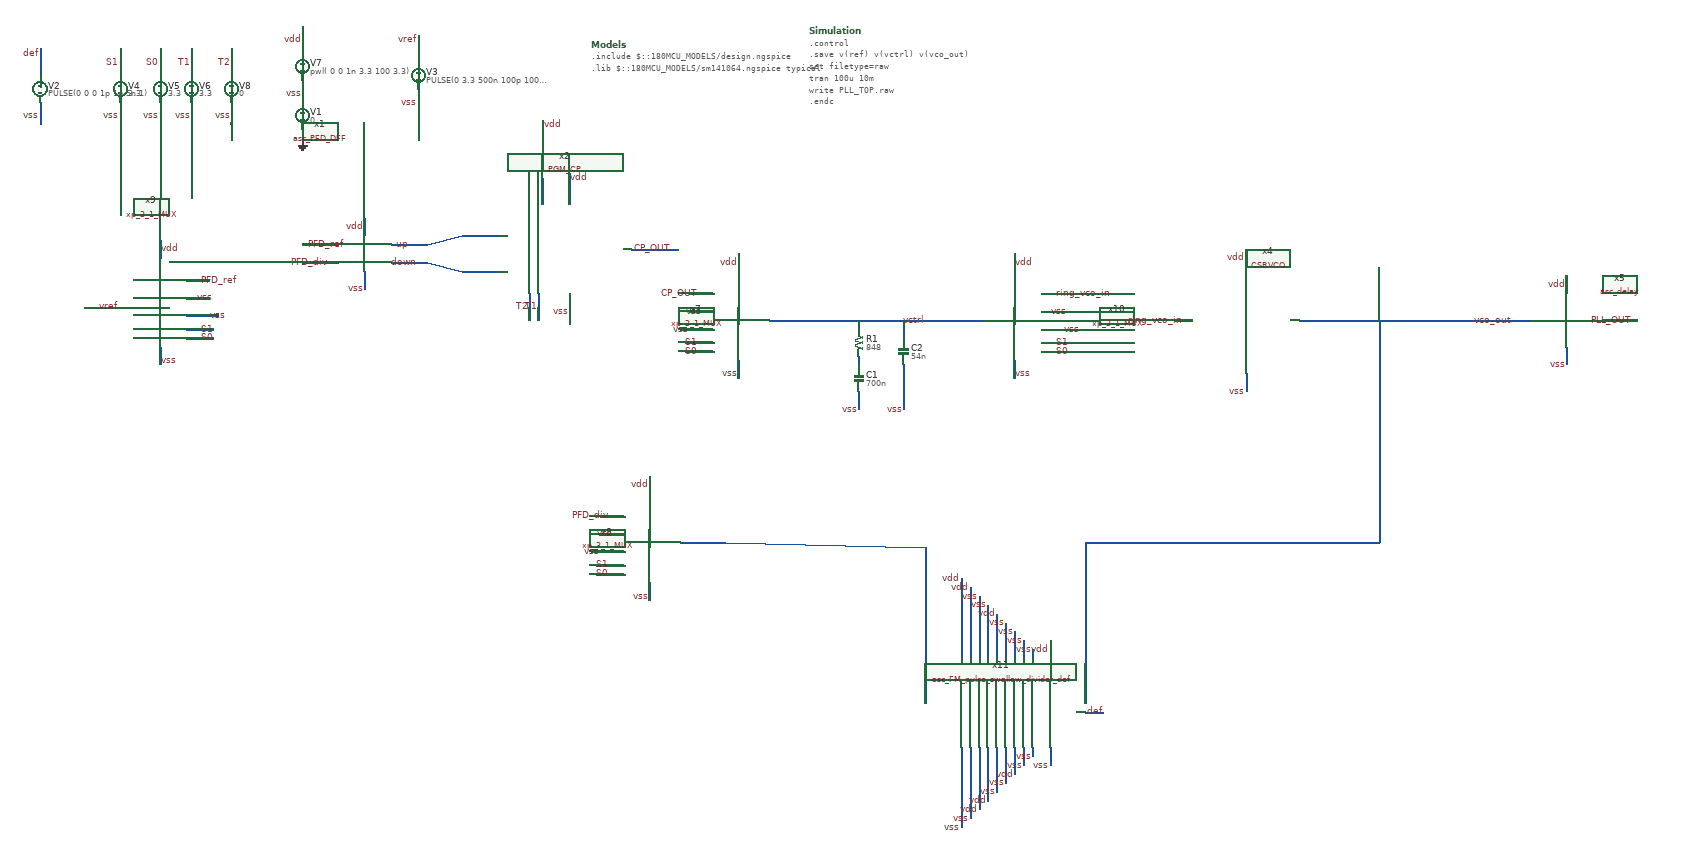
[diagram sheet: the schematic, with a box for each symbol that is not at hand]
v {xschem version=3.4.7 file_version=1.2}
G {}
K {}
V {}
S {}
E {}
N -310 -760 -310 -730 {lab=GND}
N -310 -870 -310 -820 {lab=vss}
N -310 -990 -310 -930 {lab=vdd}
N -50 -850 -50 -800 {lab=vss}
N -50 -970 -50 -910 {lab=vref}
N -270 -500 -230 -500 {lab=PFD_ref}
N -270 -460 -230 -460 {lab=PFD_div}
N -110 -500 -70 -500 {lab=up}
N -110 -460 -70 -460 {lab=down}
N -170 -560 -170 -520 {lab=vdd}
N -170 -440 -170 -400 {lab=vss}
N -70 -500 -30 -500 {lab=up}
N -70 -460 -30 -460 {lab=down}
N 840 -330 880 -330 {lab=vctrl}
N 1930 -330 1990 -330 {lab=vco_out}
N 2610 -330 2690 -330 {lab=PLL_OUT}
N 1990 -330 2070 -330 {lab=vco_out}
N 2530 -430 2530 -390 {lab=vdd}
N 2530 -270 2530 -230 {lab=vss}
N 1810 -210 1810 -170 {lab=vss}
N 1810 -490 1810 -450 {lab=vdd}
N 1650 -330 1690 -330 {lab=ring_vco_in}
N -310 -460 -270 -460 {lab=PFD_div}
N 880 -330 900 -330 {lab=vctrl}
N 900 -330 1120 -330 {lab=vctrl}
N 1040 -230 1040 -190 {lab=vss}
N 940 -170 940 -130 {lab=vss}
N 1040 -190 1040 -130 {lab=vss}
N 1040 -330 1040 -290 {lab=vctrl}
N 940 -250 940 -230 {lab=#net1}
N 940 -330 940 -310 {lab=vctrl}
N 230 -780 230 -710 {lab=vdd}
N 50 -520 90 -520 {lab=up}
N 50 -440 90 -440 {lab=down}
N 90 -520 130 -520 {lab=up}
N 90 -440 130 -440 {lab=down}
N 230 -650 230 -590 {lab=#net2}
N 290 -660 290 -590 {lab=vdd}
N 290 -390 290 -350 {lab=vss}
N -560 -820 -560 -770 {lab=vss}
N -560 -940 -560 -880 {lab=T1}
N -470 -820 -470 -770 {lab=vss}
N -470 -940 -470 -880 {lab=T2}
N 220 -390 220 -330 {lab=T1}
N 200 -390 200 -330 {lab=T2}
N 2070 -330 2450 -330 {lab=vco_out}
N -30 -500 50 -520 {lab=up}
N -30 -460 50 -440 {lab=down}
N 670 -480 670 -440 {lab=vdd}
N 670 -240 670 -200 {lab=vss}
N 430 -490 470 -490 {lab=CP_OUT}
N 470 -490 530 -490 {lab=CP_OUT}
N 560 -390 610 -390 {lab=CP_OUT}
N 560 -350 610 -350 {lab=vss}
N 540 -310 610 -310 {lab=vss}
N -720 -820 -720 -770 {lab=vss}
N -720 -940 -720 -880 {lab=S1}
N -630 -820 -630 -770 {lab=vss}
N -630 -940 -630 -880 {lab=S0}
N 550 -280 610 -280 {lab=S1}
N 550 -260 610 -260 {lab=S0}
N 740 -330 840 -330 {lab=vctrl}
N 470 20 470 60 {lab=vdd}
N 470 260 470 300 {lab=vss}
N 360 110 410 110 {lab=PFD_div}
N 360 150 410 150 {lab=vss}
N 340 190 410 190 {lab=vss}
N 350 220 410 220 {lab=S1}
N 350 240 410 240 {lab=S0}
N 540 170 640 170 {lab=#net3}
N -630 -510 -630 -470 {lab=vdd}
N -630 -270 -630 -230 {lab=vss}
N -570 -420 -520 -420 {lab=PFD_ref}
N -570 -380 -520 -380 {lab=vss}
N -570 -340 -500 -340 {lab=vss}
N -570 -310 -510 -310 {lab=S1}
N -570 -290 -510 -290 {lab=S0}
N -800 -360 -700 -360 {lab=vref}
N -310 -500 -270 -500 {lab=PFD_ref}
N 1290 -480 1290 -440 {lab=vdd}
N 1290 -240 1290 -200 {lab=vss}
N 1350 -390 1400 -390 {lab=ring_vco_in}
N 1350 -350 1400 -350 {lab=vss}
N 1350 -310 1420 -310 {lab=vss}
N 1350 -280 1410 -280 {lab=S1}
N 1350 -260 1410 -260 {lab=S0}
N 1120 -330 1220 -330 {lab=vctrl}
N 2110 -330 2110 160 {lab=vco_out}
N 2110 160 2110 170 {lab=vco_out}
N 1700 170 2110 170 {lab=vco_out}
N -900 -820 -900 -770 {lab=vss}
N -900 -940 -900 -880 {lab=def}
N 1310 630 1310 660 {lab=vss}
N 1310 660 1310 670 {lab=vss}
N 1290 630 1290 670 {lab=vdd}
N 1270 630 1270 670 {lab=vss}
N 1250 630 1250 670 {lab=vss}
N 1230 630 1230 670 {lab=vdd}
N 1210 630 1210 670 {lab=vdd}
N 1170 630 1170 660 {lab=vss}
N 1170 660 1170 670 {lab=vss}
N 1190 630 1190 670 {lab=vss}
N 1170 670 1170 770 {lab=vss}
N 1170 770 1170 790 {lab=vss}
N 1170 790 1170 810 {lab=vss}
N 1190 670 1190 790 {lab=vss}
N 1210 670 1210 770 {lab=vdd}
N 1230 670 1230 750 {lab=vdd}
N 1250 670 1250 730 {lab=vss}
N 1270 670 1270 710 {lab=vss}
N 1290 670 1290 690 {lab=vdd}
N 1330 630 1330 650 {lab=vss}
N 1450 550 1490 550 {lab=def}
N 1370 390 1370 430 {lab=vdd}
N 1370 630 1370 670 {lab=vss}
N 1330 410 1330 430 {lab=vss}
N 1310 390 1310 430 {lab=vss}
N 1290 370 1290 430 {lab=vss}
N 1270 350 1270 430 {lab=vss}
N 1250 330 1250 430 {lab=vdd}
N 1230 310 1230 430 {lab=vss}
N 1210 290 1210 430 {lab=vss}
N 1190 270 1190 430 {lab=vdd}
N 1170 250 1170 430 {lab=vdd}
N 1450 170 1450 530 {lab=vco_out}
N 1450 170 1700 170 {lab=vco_out}
N 1090 180 1090 530 {lab=#net3}
N 640 170 1090 180 {lab=#net3}
C {devices/code_shown.sym} 340 -950 0 0 {name=Models only_toplevel=false
format="tcleval( @value )"
value="
.include $::180MCU_MODELS/design.ngspice
.lib $::180MCU_MODELS/sm141064.ngspice typical
"}
C {devices/code_shown.sym} 830 -980 0 0 {name=Simulation only_toplevel=false value="
.control
.save v(ref) v(vctrl) v(vco_out)
set filetype=raw
tran 100u 10m
write PLL_TOP.raw
.endc
"}
C {devices/vsource.sym} -310 -790 0 0 {name=V1 value=0 savecurrent=false}
C {devices/gnd.sym} -310 -730 0 0 {name=l1 lab=GND}
C {devices/lab_wire.sym} -310 -840 0 0 {name=p2 sig_type=std_logic lab=vss}
C {devices/vsource.sym} -50 -880 0 0 {name=V3
value="PULSE(0 3.3 500n 100p 100p 50u 100u)"
savecurrent=false}
C {devices/lab_wire.sym} -50 -820 0 0 {name=p7 sig_type=std_logic lab=vss}
C {devices/lab_wire.sym} -310 -960 0 0 {name=p4 sig_type=std_logic lab=vdd}
C {devices/lab_wire.sym} -50 -960 0 0 {name=p8 sig_type=std_logic lab=vref}
C {libs/core_analog/asc_PFD_DFF/asc_PFD_DFF.sym} -170 -480 0 0 {name=x1}
C {devices/lab_wire.sym} -170 -400 0 0 {name=p5 sig_type=std_logic lab=vss}
C {devices/lab_wire.sym} -170 -540 0 0 {name=p6 sig_type=std_logic lab=vdd}
C {devices/lab_wire.sym} -70 -500 0 0 {name=p11 sig_type=std_logic lab=up}
C {devices/lab_wire.sym} -50 -460 0 0 {name=p12 sig_type=std_logic lab=down}
C {libs/core_analog/CSRVCO/CSRVCO.sym} 1810 -330 0 0 {name=x4}
C {libs/core_analog/asc_delay/asc_delay.sym} 2530 -330 0 0 {name=x5}
C {devices/lab_wire.sym} 1810 -170 0 0 {name=p17 sig_type=std_logic lab=vss}
C {devices/lab_wire.sym} 2530 -230 0 0 {name=p18 sig_type=std_logic lab=vss}
C {devices/lab_wire.sym} 2680 -330 0 0 {name=p19 sig_type=std_logic lab=PLL_OUT}
C {devices/lab_wire.sym} 1810 -470 0 0 {name=p20 sig_type=std_logic lab=vdd}
C {devices/lab_wire.sym} 2530 -410 0 0 {name=p21 sig_type=std_logic lab=vdd}
C {devices/lab_wire.sym} 2410 -330 0 0 {name=p25 sig_type=std_logic lab=vco_out}
C {devices/capa.sym} 940 -200 0 0 {name=C1
m=1
value=700n
footprint=1206
device="ceramic capacitor"}
C {devices/capa.sym} 1040 -260 0 0 {name=C2
m=1
value=54n
footprint=1206
device="ceramic capacitor"}
C {devices/lab_wire.sym} 1040 -130 0 0 {name=p1 sig_type=std_logic lab=vss}
C {devices/lab_wire.sym} 940 -130 0 0 {name=p3 sig_type=std_logic lab=vss}
C {devices/res.sym} 940 -280 0 0 {name=R1
value=848
footprint=1206
device=resistor
m=1}
C {isource.sym} 230 -680 0 0 {name=I1 value=100u}
C {devices/lab_wire.sym} 230 -770 2 0 {name=p36 sig_type=std_logic lab=vdd}
C {devices/lab_wire.sym} 1090 -330 0 0 {name=p13 sig_type=std_logic lab=vctrl}
C {libs/core_analog/PGM_CP.sym} 280 -490 0 0 {name=x2}
C {devices/lab_wire.sym} 290 -650 2 0 {name=p23 sig_type=std_logic lab=vdd}
C {devices/lab_wire.sym} 290 -350 0 0 {name=p24 sig_type=std_logic lab=vss}
C {devices/vsource.sym} -560 -850 0 0 {name=V6 value=3.3 savecurrent=false}
C {devices/lab_wire.sym} -560 -790 0 0 {name=p41 sig_type=std_logic lab=vss}
C {devices/lab_wire.sym} -560 -910 0 0 {name=p42 sig_type=std_logic lab=T1}
C {devices/vsource.sym} -470 -850 0 0 {name=V8 value=0 savecurrent=false}
C {devices/lab_wire.sym} -470 -790 0 0 {name=p43 sig_type=std_logic lab=vss}
C {devices/lab_wire.sym} -470 -910 0 0 {name=p44 sig_type=std_logic lab=T2}
C {devices/lab_wire.sym} 220 -360 0 0 {name=p26 sig_type=std_logic lab=T1}
C {devices/lab_wire.sym} 200 -360 0 0 {name=p27 sig_type=std_logic lab=T2}
C {libs/core_analog/xp_3_1_MUX.sym} 370 -330 0 0 {name=x7}
C {devices/lab_wire.sym} 670 -460 0 0 {name=p28 sig_type=std_logic lab=vdd}
C {devices/lab_wire.sym} 670 -210 0 0 {name=p29 sig_type=std_logic lab=vss}
C {devices/lab_wire.sym} 520 -490 0 0 {name=p31 sig_type=std_logic lab=CP_OUT}
C {devices/lab_wire.sym} 590 -350 0 0 {name=p32 sig_type=std_logic lab=vss}
C {devices/lab_wire.sym} 580 -390 0 0 {name=p33 sig_type=std_logic lab=CP_OUT}
C {devices/lab_wire.sym} 560 -310 0 0 {name=p34 sig_type=std_logic lab=vss}
C {devices/vsource.sym} -720 -850 0 0 {name=V4 value=3.3 savecurrent=false}
C {devices/lab_wire.sym} -720 -790 0 0 {name=p35 sig_type=std_logic lab=vss}
C {devices/lab_wire.sym} -720 -910 0 0 {name=p37 sig_type=std_logic lab=S1}
C {devices/vsource.sym} -630 -850 0 0 {name=V5 value=3.3 savecurrent=false}
C {devices/lab_wire.sym} -630 -790 0 0 {name=p38 sig_type=std_logic lab=vss}
C {devices/lab_wire.sym} -630 -910 0 0 {name=p39 sig_type=std_logic lab=S0}
C {devices/lab_wire.sym} 580 -280 0 0 {name=p40 sig_type=std_logic lab=S1}
C {devices/lab_wire.sym} 580 -260 0 0 {name=p45 sig_type=std_logic lab=S0}
C {libs/core_analog/xp_3_1_MUX.sym} 170 170 0 0 {name=x8}
C {devices/lab_wire.sym} 470 40 0 0 {name=p47 sig_type=std_logic lab=vdd}
C {devices/lab_wire.sym} 470 290 0 0 {name=p48 sig_type=std_logic lab=vss}
C {devices/lab_wire.sym} 390 150 0 0 {name=p49 sig_type=std_logic lab=vss}
C {devices/lab_wire.sym} 380 110 0 0 {name=p50 sig_type=std_logic lab=PFD_div}
C {devices/lab_wire.sym} 360 190 0 0 {name=p51 sig_type=std_logic lab=vss}
C {devices/lab_wire.sym} 380 220 0 0 {name=p52 sig_type=std_logic lab=S1}
C {devices/lab_wire.sym} 380 240 0 0 {name=p53 sig_type=std_logic lab=S0}
C {devices/lab_wire.sym} -250 -460 0 0 {name=p9 sig_type=std_logic lab=PFD_div}
C {libs/core_analog/xp_3_1_MUX.sym} -330 -360 0 1 {name=x9}
C {devices/lab_wire.sym} -630 -490 0 1 {name=p10 sig_type=std_logic lab=vdd}
C {devices/lab_wire.sym} -630 -240 0 1 {name=p55 sig_type=std_logic lab=vss}
C {devices/lab_wire.sym} -550 -380 0 1 {name=p56 sig_type=std_logic lab=vss}
C {devices/lab_wire.sym} -540 -420 0 1 {name=p57 sig_type=std_logic lab=PFD_ref}
C {devices/lab_wire.sym} -520 -340 0 1 {name=p58 sig_type=std_logic lab=vss}
C {devices/lab_wire.sym} -540 -310 0 1 {name=p59 sig_type=std_logic lab=S1}
C {devices/lab_wire.sym} -540 -290 0 1 {name=p60 sig_type=std_logic lab=S0}
C {devices/lab_wire.sym} -300 -500 0 1 {name=p62 sig_type=std_logic lab=PFD_ref}
C {devices/lab_wire.sym} -770 -360 0 1 {name=p63 sig_type=std_logic lab=vref}
C {libs/core_analog/xp_3_1_MUX.sym} 1590 -330 0 1 {name=x10}
C {devices/lab_wire.sym} 1290 -460 0 1 {name=p46 sig_type=std_logic lab=vdd}
C {devices/lab_wire.sym} 1290 -210 0 1 {name=p64 sig_type=std_logic lab=vss}
C {devices/lab_wire.sym} 1370 -350 0 1 {name=p65 sig_type=std_logic lab=vss}
C {devices/lab_wire.sym} 1380 -390 0 1 {name=p66 sig_type=std_logic lab=ring_vco_in}
C {devices/lab_wire.sym} 1400 -310 0 1 {name=p67 sig_type=std_logic lab=vss}
C {devices/lab_wire.sym} 1380 -280 0 1 {name=p68 sig_type=std_logic lab=S1}
C {devices/lab_wire.sym} 1380 -260 0 1 {name=p69 sig_type=std_logic lab=S0}
C {devices/lab_wire.sym} 1670 -330 2 1 {name=p71 sig_type=std_logic lab=ring_vco_in}
C {devices/vsource.sym} -310 -900 0 0 {name=V7 value="pwl( 0 0 1n 3.3 100 3.3)" savecurrent=false}
C {devices/vsource.sym} -900 -850 0 0 {name=V2
value="PULSE(0 0 0 1p 1p 5n 1)"
savecurrent=false}
C {devices/lab_wire.sym} -900 -790 0 0 {name=p15 sig_type=std_logic lab=vss}
C {devices/lab_wire.sym} -900 -930 0 0 {name=p22 sig_type=std_logic lab=def}
C {devices/lab_wire.sym} 1370 410 0 0 {name=p70 sig_type=std_logic lab=vdd}
C {devices/lab_wire.sym} 1370 670 0 0 {name=p72 sig_type=std_logic lab=vss}
C {libs/core_analog/asc_FM_pulse_swallow_divider_def/asc_FM_pulse_swallow_divider_def.sym} 1270 530 0 0 {name=x11}
C {devices/lab_wire.sym} 1490 550 0 0 {name=p75 sig_type=std_logic lab=def}
C {devices/lab_wire.sym} 1330 650 0 0 {name=p76 sig_type=std_logic lab=vss}
C {devices/lab_wire.sym} 1310 670 0 0 {name=p77 sig_type=std_logic lab=vss}
C {devices/lab_wire.sym} 1290 690 0 0 {name=p78 sig_type=std_logic lab=vdd}
C {devices/lab_wire.sym} 1270 710 0 0 {name=p79 sig_type=std_logic lab=vss}
C {devices/lab_wire.sym} 1250 730 0 0 {name=p80 sig_type=std_logic lab=vss}
C {devices/lab_wire.sym} 1230 750 0 0 {name=p81 sig_type=std_logic lab=vdd}
C {devices/lab_wire.sym} 1210 770 0 0 {name=p82 sig_type=std_logic lab=vdd}
C {devices/lab_wire.sym} 1190 790 0 0 {name=p83 sig_type=std_logic lab=vss}
C {devices/lab_wire.sym} 1170 810 0 0 {name=p84 sig_type=std_logic lab=vss}
C {devices/lab_wire.sym} 1330 410 0 0 {name=p85 sig_type=std_logic lab=vss}
C {devices/lab_wire.sym} 1310 390 0 0 {name=p86 sig_type=std_logic lab=vss}
C {devices/lab_wire.sym} 1290 370 0 0 {name=p87 sig_type=std_logic lab=vss}
C {devices/lab_wire.sym} 1270 350 0 0 {name=p88 sig_type=std_logic lab=vss}
C {devices/lab_wire.sym} 1250 330 0 0 {name=p89 sig_type=std_logic lab=vdd}
C {devices/lab_wire.sym} 1230 310 0 0 {name=p90 sig_type=std_logic lab=vss}
C {devices/lab_wire.sym} 1210 290 0 0 {name=p91 sig_type=std_logic lab=vss}
C {devices/lab_wire.sym} 1190 270 0 0 {name=p92 sig_type=std_logic lab=vdd}
C {devices/lab_wire.sym} 1170 250 0 0 {name=p93 sig_type=std_logic lab=vdd}
